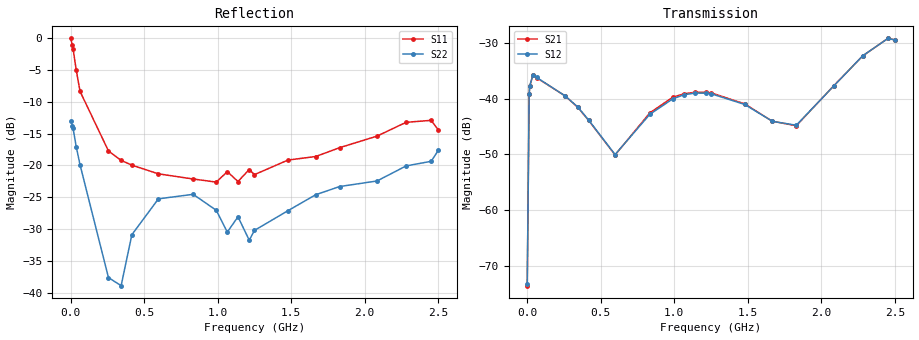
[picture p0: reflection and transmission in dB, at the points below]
#  HZ  S  MA  R  50.00
! Rohde & Schwarz Vector Network Analyzer
! Rohde-Schwarz,ZNL6-2Port,1323001206101378,1.50.1.34-21.10.1.104
! Created: UTC 3/3/2025, 5:30:09 AM
! freq[Hz]  mag:S11  ang:S11  mag:S21  ang:S21  mag:S12  ang:S12  mag:S22  ang:S22
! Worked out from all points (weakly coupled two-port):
!   10001 points, 5 kHz to 2.5 GHz, reference 50 ohm
!   highest |S21| = -29.22 dB at 2.452 GHz (marker M1); lowest = -73.5 dB at 5 kHz (marker M2)
!   lowest |S11| = -22.6 dB at 990.5 MHz (marker M3), VSWR 1.16, Z = 57.3 - j3 ohm
!   |S11| at or under -10 dB: 80.08 MHz to end of sweep
!   |S22| runs from -39.0 to -12.8 dB; largest |S21 - S12| = 0.0034
!   S11 on the Smith chart (normalised r, x): 5 kHz: 0.00, -0.00; 17 MHz: 0.11, +0.32; 64.5 MHz: 0.64, +0.55; 1.478 GHz: 1.11, -0.20; 2.5 GHz: 0.74, +0.20
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5000  0.9938 -179.6  0.0002108 -16.1  0.0002183 -21.6  0.2241 -177.8
1.300497e7  0.8797 151.6  0.01097 -152.7  0.01102 -152.0  0.2054 150.9
1.700497e7  0.8226 144.4  0.01293 -169.5  0.01297 -169.4  0.1947 142.9
3.850492e7  0.5588 120.0  0.01613 125.2  0.01625 126.4  0.1399 106.7
6.450487e7  0.3808 105.1  0.01533 80.1  0.01543 81.2  0.1007 75.6
2.575045e8  0.1297 59.0  0.01054 -25.8  0.01056 -26.2  0.01313 -78.4
3.437543e8  0.1094 48.5  0.008339 -46.5  0.008396 -48.2  0.01134 -177.9
4.167542e8  0.1003 36.9  0.00638 -59.7  0.00643 -61.3  0.02853 125.4
5.972538e8  0.08575 14.3  0.003123 -41.8  0.003151 -44.9  0.05455 57.8
8.335033e8  0.07808 -5.4  0.007442 -32.3  0.007222 -33.4  0.05921 1.6
9.90503e8  0.07383 -20.6  0.01029 -59.9  0.009954 -62.5  0.04433 -21.3
1.065503e9  0.0892 -24.9  0.01101 -75.5  0.0108 -77.4  0.02989 -25.2
1.138253e9  0.07464 -33.2  0.01137 -90.9  0.01119 -92.4  0.03943 -17.3
1.214753e9  0.0927 -36.1  0.01135 -107.2  0.01116 -108.3  0.02581 -2.6
1.250002e9  0.08449 -37.9  0.01125 -114.5  0.01104 -116.4  0.03081 -15.7
1.478002e9  0.11 -55.8  0.00896 -165.5  0.008856 -167.3  0.04403 -37.1
1.666752e9  0.1173 -76.5  0.006259 138.5  0.006251 136.8  0.05877 -71.3
1.829251e9  0.1376 -94.2  0.005708 65.6  0.005765 64.7  0.06814 -111.1
2.083501e9  0.1696 -121.4  0.013 -25.3  0.01293 -25.6  0.07534 -171.7
2.28075e9  0.2176 -146.6  0.02407 -73.3  0.02414 -73.9  0.09886 149.6
2.452e9  0.2257 152.3  0.03458 -127.8  0.03449 -127.8  0.1076 120.9
2.5e9  0.1896 136.5  0.0335 -143.7  0.03345 -144.5  0.1312 115.6
